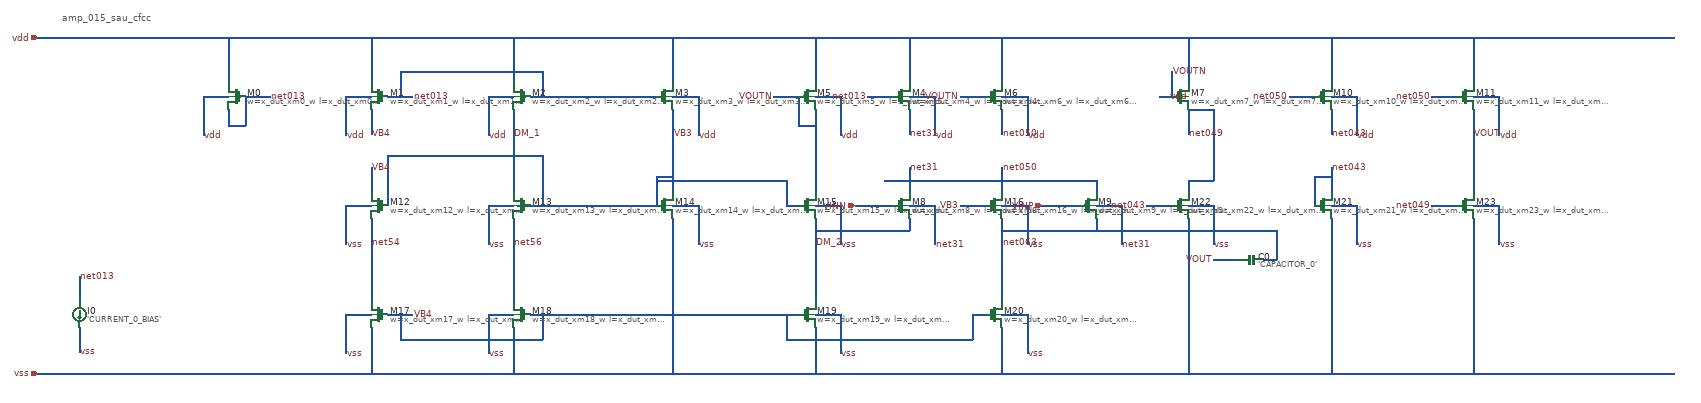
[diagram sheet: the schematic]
v {xschem version=3.4.6 file_version=1.2}
G {}
K {}
V {}
S {}
E {}
T {amp_015_sau_cfcc} -1775 -200 0 0 0.4 0.4 {}
C {devices/capa_np.sym} 1060 390 1 0 {name=C0 value='CAPACITOR_0'}
C {devices/isource_np.sym} -1735 520 0 0 {name=I0 value='CURRENT_0_BIAS'}
C {devices/sg13_lv_pmos_np.sym} -1360 0 0 1 {name=M0 model=sg13_lv_pmos spiceprefix=X w=x_dut_xm0_w l=x_dut_xm0_l m=x_dut_xm0_m}
C {devices/sg13_lv_pmos_np.sym} -1020 0 0 1 {name=M1 model=sg13_lv_pmos spiceprefix=X w=x_dut_xm1_w l=x_dut_xm1_l m=x_dut_xm1_m}
C {devices/sg13_lv_pmos_np.sym} 1230 0 0 0 {name=M10 model=sg13_lv_pmos spiceprefix=X w=x_dut_xm10_w l=x_dut_xm10_l m=x_dut_xm10_m}
C {devices/sg13_lv_pmos_np.sym} 1570 0 0 0 {name=M11 model=sg13_lv_pmos spiceprefix=X w=x_dut_xm11_w l=x_dut_xm11_l m=x_dut_xm11_m}
C {devices/sg13_lv_nmos_np.sym} -1020 260 0 1 {name=M12 model=sg13_lv_nmos spiceprefix=X w=x_dut_xm12_w l=x_dut_xm12_l m=x_dut_xm12_m}
C {devices/sg13_lv_nmos_np.sym} -680 260 0 1 {name=M13 model=sg13_lv_nmos spiceprefix=X w=x_dut_xm13_w l=x_dut_xm13_l m=x_dut_xm13_m}
C {devices/sg13_lv_nmos_np.sym} -340 260 0 0 {name=M14 model=sg13_lv_nmos spiceprefix=X w=x_dut_xm14_w l=x_dut_xm14_l m=x_dut_xm14_m}
C {devices/sg13_lv_nmos_np.sym} 0 260 0 0 {name=M15 model=sg13_lv_nmos spiceprefix=X w=x_dut_xm15_w l=x_dut_xm15_l m=x_dut_xm15_m}
C {devices/sg13_lv_nmos_np.sym} 445 260 0 0 {name=M16 model=sg13_lv_nmos spiceprefix=X w=x_dut_xm16_w l=x_dut_xm16_l m=x_dut_xm16_m}
C {devices/sg13_lv_nmos_np.sym} -1020 520 0 1 {name=M17 model=sg13_lv_nmos spiceprefix=X w=x_dut_xm17_w l=x_dut_xm17_l m=x_dut_xm17_m}
C {devices/sg13_lv_nmos_np.sym} -680 520 0 1 {name=M18 model=sg13_lv_nmos spiceprefix=X w=x_dut_xm18_w l=x_dut_xm18_l m=x_dut_xm18_m}
C {devices/sg13_lv_nmos_np.sym} 0 520 0 0 {name=M19 model=sg13_lv_nmos spiceprefix=X w=x_dut_xm19_w l=x_dut_xm19_l m=x_dut_xm19_m}
C {devices/sg13_lv_pmos_np.sym} -680 0 0 1 {name=M2 model=sg13_lv_pmos spiceprefix=X w=x_dut_xm2_w l=x_dut_xm2_l m=x_dut_xm2_m}
C {devices/sg13_lv_nmos_np.sym} 445 520 0 0 {name=M20 model=sg13_lv_nmos spiceprefix=X w=x_dut_xm20_w l=x_dut_xm20_l m=x_dut_xm20_m}
C {devices/sg13_lv_nmos_np.sym} 1230 260 0 0 {name=M21 model=sg13_lv_nmos spiceprefix=X w=x_dut_xm21_w l=x_dut_xm21_l m=x_dut_xm21_m}
C {devices/sg13_lv_nmos_np.sym} 890 260 0 0 {name=M22 model=sg13_lv_nmos spiceprefix=X w=x_dut_xm22_w l=x_dut_xm22_l m=x_dut_xm22_m}
C {devices/sg13_lv_nmos_np.sym} 1570 260 0 0 {name=M23 model=sg13_lv_nmos spiceprefix=X w=x_dut_xm23_w l=x_dut_xm23_l m=x_dut_xm23_m}
C {devices/sg13_lv_pmos_np.sym} -340 0 0 0 {name=M3 model=sg13_lv_pmos spiceprefix=X w=x_dut_xm3_w l=x_dut_xm3_l m=x_dut_xm3_m}
C {devices/sg13_lv_pmos_np.sym} 225 0 0 0 {name=M4 model=sg13_lv_pmos spiceprefix=X w=x_dut_xm4_w l=x_dut_xm4_l m=x_dut_xm4_m}
C {devices/sg13_lv_pmos_np.sym} 0 0 0 0 {name=M5 model=sg13_lv_pmos spiceprefix=X w=x_dut_xm5_w l=x_dut_xm5_l m=x_dut_xm5_m}
C {devices/sg13_lv_pmos_np.sym} 445 0 0 0 {name=M6 model=sg13_lv_pmos spiceprefix=X w=x_dut_xm6_w l=x_dut_xm6_l m=x_dut_xm6_m}
C {devices/sg13_lv_pmos_np.sym} 890 0 0 0 {name=M7 model=sg13_lv_pmos spiceprefix=X w=x_dut_xm7_w l=x_dut_xm7_l m=x_dut_xm7_m}
C {devices/sg13_lv_pmos_np.sym} 225 260 0 0 {name=M8 model=sg13_lv_pmos spiceprefix=X w=x_dut_xm8_w l=x_dut_xm8_l m=x_dut_xm8_m}
C {devices/sg13_lv_pmos_np.sym} 670 260 0 0 {name=M9 model=sg13_lv_pmos spiceprefix=X w=x_dut_xm9_w l=x_dut_xm9_l m=x_dut_xm9_m}
N -1735 430 -1735 490 {}
N -1735 550 -1735 610 {}
N -1440 0 -1440 94 {}
N -1380 -140 -1380 -30 {}
N -1380 30 -1380 70 {}
N -1340 0 -1340 70 {}
N -1100 0 -1100 94 {}
N -1100 260 -1100 354 {}
N -1100 520 -1100 614 {}
N -1040 -140 -1040 -30 {}
N -1040 30 -1040 90 {}
N -1040 170 -1040 230 {}
N -1040 290 -1040 490 {}
N -1040 550 -1040 660 {}
N -1000 140 -1000 260 {}
N -970 -60 -970 0 {}
N -970 520 -970 580 {}
N -760 0 -760 94 {}
N -760 260 -760 354 {}
N -760 520 -760 614 {}
N -700 -140 -700 -30 {}
N -700 30 -700 230 {}
N -700 290 -700 490 {}
N -700 550 -700 660 {}
N -630 -60 -630 0 {}
N -630 140 -630 260 {}
N -630 520 -630 580 {}
N -360 190 -360 260 {}
N -320 -140 -320 -30 {}
N -320 30 -320 200 {}
N -320 200 -320 230 {}
N -320 290 -320 660 {}
N -260 0 -260 94 {}
N -260 260 -260 354 {}
N -50 200 -50 260 {}
N -50 520 -50 580 {}
N -20 0 -20 70 {}
N 20 -140 20 -30 {}
N 20 30 20 230 {}
N 20 290 20 490 {}
N 20 550 20 660 {}
N 80 0 80 94 {}
N 80 260 80 354 {}
N 80 520 80 614 {}
N 245 -140 245 -30 {}
N 245 30 245 90 {}
N 245 170 245 200 {}
N 245 200 245 230 {}
N 245 290 245 320 {}
N 305 0 305 94 {}
N 305 260 305 354 {}
N 395 520 395 580 {}
N 465 -140 465 -30 {}
N 465 30 465 90 {}
N 465 170 465 230 {}
N 465 290 465 490 {}
N 465 550 465 660 {}
N 525 0 525 94 {}
N 525 260 525 354 {}
N 525 520 525 614 {}
N 690 200 690 230 {}
N 690 290 690 320 {}
N 750 260 750 354 {}
N 870 -60 870 0 {}
N 910 -140 910 -30 {}
N 910 30 910 90 {}
N 910 200 910 230 {}
N 910 290 910 660 {}
N 970 30 970 200 {}
N 970 260 970 354 {}
N 1120 320 1120 390 {}
N 1210 190 1210 260 {}
N 1250 -140 1250 -30 {}
N 1250 30 1250 90 {}
N 1250 170 1250 230 {}
N 1250 290 1250 660 {}
N 1310 0 1310 94 {}
N 1310 260 1310 354 {}
N 1590 -140 1590 -30 {}
N 1590 30 1590 230 {}
N 1590 290 1590 660 {}
N 1650 0 1650 94 {}
N 1650 260 1650 354 {}
N -1835 -140 2070 -140 {}
N -970 -60 -630 -60 {}
N -1440 0 -1380 0 {}
N -1340 0 -1280 0 {}
N -1100 0 -1040 0 {}
N -1000 0 -940 0 {}
N -760 0 -700 0 {}
N -660 0 -360 0 {}
N -320 0 -260 0 {}
N -80 0 -20 0 {}
N 20 0 80 0 {}
N 145 0 205 0 {}
N 245 0 305 0 {}
N 365 0 425 0 {}
N 465 0 525 0 {}
N 840 0 870 0 {}
N 1150 0 1210 0 {}
N 1250 0 1310 0 {}
N 1490 0 1550 0 {}
N 1590 0 1650 0 {}
N 910 30 970 30 {}
N -1380 70 -1340 70 {}
N -20 70 20 70 {}
N -1000 140 -630 140 {}
N -360 190 -320 190 {}
N 1210 190 1250 190 {}
N -360 200 -50 200 {}
N 185 200 690 200 {}
N 910 200 970 200 {}
N -1100 260 -1040 260 {}
N -760 260 -700 260 {}
N -690 260 -360 260 {}
N -320 260 -260 260 {}
N -50 260 -20 260 {}
N 20 260 80 260 {}
N 115 260 205 260 {}
N 245 260 305 260 {}
N 365 260 425 260 {}
N 465 260 525 260 {}
N 560 260 650 260 {}
N 690 260 750 260 {}
N 810 260 870 260 {}
N 910 260 970 260 {}
N 1250 260 1310 260 {}
N 1490 260 1550 260 {}
N 1590 260 1650 260 {}
N 20 320 245 320 {}
N 465 320 1120 320 {}
N 970 390 1030 390 {}
N 1090 390 1120 390 {}
N -1100 520 -1040 520 {}
N -1000 520 -940 520 {}
N -760 520 -700 520 {}
N -660 520 -20 520 {}
N 20 520 80 520 {}
N 395 520 425 520 {}
N 465 520 525 520 {}
N -970 580 -630 580 {}
N -50 580 395 580 {}
N -1835 660 2070 660 {}
C {devices/lab_wire.sym} -700 90 2 0 {name=l0 lab=DM_1}
C {devices/lab_wire.sym} 20 350 2 0 {name=l1 lab=DM_2}
C {devices/lab_wire.sym} -320 90 2 0 {name=l2 lab=VB3}
C {devices/lab_wire.sym} 365 260 0 0 {name=l3 lab=VB3}
C {devices/lab_wire.sym} -1040 90 2 0 {name=l4 lab=VB4}
C {devices/lab_wire.sym} -1040 170 0 1 {name=l5 lab=VB4}
C {devices/lab_wire.sym} -940 520 0 1 {name=l6 lab=VB4}
C {devices/lab_wire.sym} 970 390 0 0 {name=l7 lab=VOUT}
C {devices/lab_wire.sym} 1590 90 2 0 {name=l8 lab=VOUT}
C {devices/lab_wire.sym} -80 0 0 0 {name=l9 lab=VOUTN}
C {devices/lab_wire.sym} 365 0 0 0 {name=l10 lab=VOUTN}
C {devices/lab_wire.sym} 870 -60 0 1 {name=l11 lab=VOUTN}
C {devices/lab_wire.sym} -1280 0 0 1 {name=l12 lab=net013}
C {devices/lab_wire.sym} -940 0 0 1 {name=l13 lab=net013}
C {devices/lab_wire.sym} 145 0 0 0 {name=l14 lab=net013}
C {devices/lab_wire.sym} 810 260 0 0 {name=l15 lab=net043}
C {devices/lab_wire.sym} 1250 170 0 1 {name=l16 lab=net043}
C {devices/lab_wire.sym} 1250 90 2 0 {name=l17 lab=net043}
C {devices/lab_wire.sym} 910 90 2 0 {name=l18 lab=net049}
C {devices/lab_wire.sym} 1490 260 0 0 {name=l19 lab=net049}
C {devices/lab_wire.sym} 465 90 2 0 {name=l20 lab=net050}
C {devices/lab_wire.sym} 465 170 0 1 {name=l21 lab=net050}
C {devices/lab_wire.sym} 1150 0 0 0 {name=l22 lab=net050}
C {devices/lab_wire.sym} 1490 0 0 0 {name=l23 lab=net050}
C {devices/lab_wire.sym} 465 350 2 0 {name=l24 lab=net063}
C {devices/lab_wire.sym} 245 90 2 0 {name=l25 lab=net31}
C {devices/lab_wire.sym} 245 170 0 1 {name=l26 lab=net31}
C {devices/lab_wire.sym} -1040 350 2 0 {name=l27 lab=net54}
C {devices/lab_wire.sym} -700 350 2 0 {name=l28 lab=net56}
C {devices/lab_wire.sym} 305 354 2 0 {name=l29 lab=net31}
C {devices/lab_wire.sym} 750 354 2 0 {name=l30 lab=net31}
C {devices/lab_wire.sym} -1440 94 2 0 {name=l31 lab=vdd}
C {devices/lab_wire.sym} -1100 94 2 0 {name=l32 lab=vdd}
C {devices/lab_wire.sym} 1310 94 2 0 {name=l33 lab=vdd}
C {devices/lab_wire.sym} 1650 94 2 0 {name=l34 lab=vdd}
C {devices/lab_wire.sym} -760 94 2 0 {name=l35 lab=vdd}
C {devices/lab_wire.sym} -260 94 2 0 {name=l36 lab=vdd}
C {devices/lab_wire.sym} 305 94 2 0 {name=l37 lab=vdd}
C {devices/lab_wire.sym} 80 94 2 0 {name=l38 lab=vdd}
C {devices/lab_wire.sym} 525 94 2 0 {name=l39 lab=vdd}
C {devices/lab_wire.sym} 910 0 0 0 {name=l40 lab=vdd}
C {devices/lab_wire.sym} -1100 354 2 0 {name=l41 lab=vss}
C {devices/lab_wire.sym} -760 354 2 0 {name=l42 lab=vss}
C {devices/lab_wire.sym} -260 354 2 0 {name=l43 lab=vss}
C {devices/lab_wire.sym} 80 354 2 0 {name=l44 lab=vss}
C {devices/lab_wire.sym} 525 354 2 0 {name=l45 lab=vss}
C {devices/lab_wire.sym} -1100 614 2 0 {name=l46 lab=vss}
C {devices/lab_wire.sym} -760 614 2 0 {name=l47 lab=vss}
C {devices/lab_wire.sym} 80 614 2 0 {name=l48 lab=vss}
C {devices/lab_wire.sym} 525 614 2 0 {name=l49 lab=vss}
C {devices/lab_wire.sym} 1310 354 2 0 {name=l50 lab=vss}
C {devices/lab_wire.sym} 970 354 2 0 {name=l51 lab=vss}
C {devices/lab_wire.sym} 1650 354 2 0 {name=l52 lab=vss}
C {devices/lab_wire.sym} -1735 430 0 1 {name=l53 lab=net013}
C {devices/lab_wire.sym} -1735 610 2 0 {name=l54 lab=vss}
C {devices/ipin.sym} 115 260 0 0 {name=p0 lab=VINN}
C {devices/ipin.sym} 560 260 0 0 {name=p1 lab=VINP}
C {devices/iopin.sym} -1835 -140 0 0 {name=p2 lab=vdd}
C {devices/iopin.sym} -1835 660 0 0 {name=p3 lab=vss}
